VERSION 5.7 ;
  NOWIREEXTENSIONATPIN ON ;
  DIVIDERCHAR "/" ;
  BUSBITCHARS "[]" ;
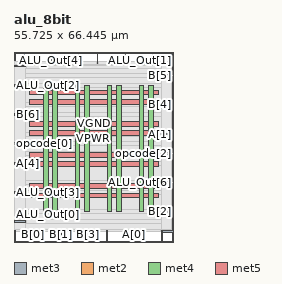
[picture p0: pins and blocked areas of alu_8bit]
MACRO alu_8bit
  CLASS BLOCK ;
  FOREIGN alu_8bit ;
  ORIGIN 0.000 0.000 ;
  SIZE 55.725 BY 66.445 ;
  PIN ALU_Out[0]
    DIRECTION OUTPUT TRISTATE ;
    USE SIGNAL ;
    ANTENNADIFFAREA 0.795200 ;
    PORT
      LAYER met3 ;
        RECT 0.000 6.840 4.000 7.440 ;
    END
  END ALU_Out[0]
  PIN ALU_Out[1]
    DIRECTION OUTPUT TRISTATE ;
    USE SIGNAL ;
    ANTENNADIFFAREA 0.795200 ;
    PORT
      LAYER met2 ;
        RECT 54.830 62.445 55.110 66.445 ;
    END
  END ALU_Out[1]
  PIN ALU_Out[2]
    DIRECTION OUTPUT TRISTATE ;
    USE SIGNAL ;
    ANTENNADIFFAREA 0.795200 ;
    PORT
      LAYER met3 ;
        RECT 0.000 54.440 4.000 55.040 ;
    END
  END ALU_Out[2]
  PIN ALU_Out[3]
    DIRECTION OUTPUT TRISTATE ;
    USE SIGNAL ;
    ANTENNADIFFAREA 0.795200 ;
    PORT
      LAYER met3 ;
        RECT 0.000 17.040 4.000 17.640 ;
    END
  END ALU_Out[3]
  PIN ALU_Out[4]
    DIRECTION OUTPUT TRISTATE ;
    USE SIGNAL ;
    ANTENNADIFFAREA 0.795200 ;
    PORT
      LAYER met2 ;
        RECT 12.970 62.445 13.250 66.445 ;
    END
  END ALU_Out[4]
  PIN ALU_Out[5]
    DIRECTION OUTPUT TRISTATE ;
    USE SIGNAL ;
    ANTENNADIFFAREA 0.795200 ;
    PORT
      LAYER met2 ;
        RECT 22.630 62.445 22.910 66.445 ;
    END
  END ALU_Out[5]
  PIN ALU_Out[6]
    DIRECTION OUTPUT TRISTATE ;
    USE SIGNAL ;
    ANTENNADIFFAREA 0.795200 ;
    PORT
      LAYER met3 ;
        RECT 51.725 20.440 55.725 21.040 ;
    END
  END ALU_Out[6]
  PIN ALU_Out[7]
    DIRECTION OUTPUT TRISTATE ;
    USE SIGNAL ;
    ANTENNADIFFAREA 0.795200 ;
    PORT
      LAYER met2 ;
        RECT 48.390 62.445 48.670 66.445 ;
    END
  END ALU_Out[7]
  PIN A[0]
    DIRECTION INPUT ;
    USE SIGNAL ;
    ANTENNAGATEAREA 0.196500 ;
    PORT
      LAYER met2 ;
        RECT 41.950 0.000 42.230 4.000 ;
    END
  END A[0]
  PIN A[1]
    DIRECTION INPUT ;
    USE SIGNAL ;
    ANTENNAGATEAREA 0.213000 ;
    PORT
      LAYER met3 ;
        RECT 51.725 37.440 55.725 38.040 ;
    END
  END A[1]
  PIN A[2]
    DIRECTION INPUT ;
    USE SIGNAL ;
    ANTENNAGATEAREA 0.213000 ;
    PORT
      LAYER met2 ;
        RECT 38.730 62.445 39.010 66.445 ;
    END
  END A[2]
  PIN A[3]
    DIRECTION INPUT ;
    USE SIGNAL ;
    ANTENNAGATEAREA 0.196500 ;
    PORT
      LAYER met3 ;
        RECT 51.725 3.440 55.725 4.040 ;
    END
  END A[3]
  PIN A[4]
    DIRECTION INPUT ;
    USE SIGNAL ;
    ANTENNAGATEAREA 0.196500 ;
    PORT
      LAYER met3 ;
        RECT 0.000 27.240 4.000 27.840 ;
    END
  END A[4]
  PIN A[5]
    DIRECTION INPUT ;
    USE SIGNAL ;
    ANTENNAGATEAREA 0.196500 ;
    PORT
      LAYER met2 ;
        RECT 3.310 62.445 3.590 66.445 ;
    END
  END A[5]
  PIN A[6]
    DIRECTION INPUT ;
    USE SIGNAL ;
    ANTENNAGATEAREA 0.196500 ;
    PORT
      LAYER met2 ;
        RECT 51.610 0.000 51.890 4.000 ;
    END
  END A[6]
  PIN A[7]
    DIRECTION INPUT ;
    USE SIGNAL ;
    ANTENNAGATEAREA 0.159000 ;
    PORT
      LAYER met2 ;
        RECT 0.090 0.000 0.370 4.000 ;
    END
  END A[7]
  PIN B[0]
    DIRECTION INPUT ;
    USE SIGNAL ;
    ANTENNAGATEAREA 0.196500 ;
    PORT
      LAYER met2 ;
        RECT 6.530 0.000 6.810 4.000 ;
    END
  END B[0]
  PIN B[1]
    DIRECTION INPUT ;
    USE SIGNAL ;
    ANTENNAGATEAREA 0.126000 ;
    PORT
      LAYER met2 ;
        RECT 16.190 0.000 16.470 4.000 ;
    END
  END B[1]
  PIN B[2]
    DIRECTION INPUT ;
    USE SIGNAL ;
    ANTENNAGATEAREA 0.126000 ;
    PORT
      LAYER met3 ;
        RECT 51.725 10.240 55.725 10.840 ;
    END
  END B[2]
  PIN B[3]
    DIRECTION INPUT ;
    USE SIGNAL ;
    ANTENNAGATEAREA 0.196500 ;
    PORT
      LAYER met2 ;
        RECT 25.850 0.000 26.130 4.000 ;
    END
  END B[3]
  PIN B[4]
    DIRECTION INPUT ;
    USE SIGNAL ;
    ANTENNAGATEAREA 0.196500 ;
    PORT
      LAYER met3 ;
        RECT 51.725 47.640 55.725 48.240 ;
    END
  END B[4]
  PIN B[5]
    DIRECTION INPUT ;
    USE SIGNAL ;
    ANTENNAGATEAREA 0.196500 ;
    PORT
      LAYER met3 ;
        RECT 51.725 57.840 55.725 58.440 ;
    END
  END B[5]
  PIN B[6]
    DIRECTION INPUT ;
    USE SIGNAL ;
    ANTENNAGATEAREA 0.196500 ;
    PORT
      LAYER met3 ;
        RECT 0.000 44.240 4.000 44.840 ;
    END
  END B[6]
  PIN B[7]
    DIRECTION INPUT ;
    USE SIGNAL ;
    ANTENNAGATEAREA 0.159000 ;
    PORT
      LAYER met2 ;
        RECT 29.070 62.445 29.350 66.445 ;
    END
  END B[7]
  PIN CarryOut
    DIRECTION OUTPUT TRISTATE ;
    USE SIGNAL ;
    ANTENNADIFFAREA 0.795200 ;
    PORT
      LAYER met2 ;
        RECT 32.290 0.000 32.570 4.000 ;
    END
  END CarryOut
  PIN VGND
    DIRECTION INOUT ;
    USE GROUND ;
    PORT
      LAYER met4 ;
        RECT 13.595 10.640 15.195 54.640 ;
    END
    PORT
      LAYER met4 ;
        RECT 24.750 10.640 26.350 54.640 ;
    END
    PORT
      LAYER met4 ;
        RECT 35.905 10.640 37.505 54.640 ;
    END
    PORT
      LAYER met4 ;
        RECT 47.060 10.640 48.660 54.640 ;
    END
    PORT
      LAYER met5 ;
        RECT 5.280 18.815 50.380 20.415 ;
    END
    PORT
      LAYER met5 ;
        RECT 5.280 29.690 50.380 31.290 ;
    END
    PORT
      LAYER met5 ;
        RECT 5.280 40.565 50.380 42.165 ;
    END
    PORT
      LAYER met5 ;
        RECT 5.280 51.440 50.380 53.040 ;
    END
  END VGND
  PIN VPWR
    DIRECTION INOUT ;
    USE POWER ;
    PORT
      LAYER met4 ;
        RECT 10.295 10.640 11.895 54.640 ;
    END
    PORT
      LAYER met4 ;
        RECT 21.450 10.640 23.050 54.640 ;
    END
    PORT
      LAYER met4 ;
        RECT 32.605 10.640 34.205 54.640 ;
    END
    PORT
      LAYER met4 ;
        RECT 43.760 10.640 45.360 54.640 ;
    END
    PORT
      LAYER met5 ;
        RECT 5.280 15.515 50.380 17.115 ;
    END
    PORT
      LAYER met5 ;
        RECT 5.280 26.390 50.380 27.990 ;
    END
    PORT
      LAYER met5 ;
        RECT 5.280 37.265 50.380 38.865 ;
    END
    PORT
      LAYER met5 ;
        RECT 5.280 48.140 50.380 49.740 ;
    END
  END VPWR
  PIN opcode[0]
    DIRECTION INPUT ;
    USE SIGNAL ;
    ANTENNAGATEAREA 0.213000 ;
    PORT
      LAYER met3 ;
        RECT 0.000 34.040 4.000 34.640 ;
    END
  END opcode[0]
  PIN opcode[1]
    DIRECTION INPUT ;
    USE SIGNAL ;
    ANTENNAGATEAREA 0.213000 ;
    PORT
      LAYER met3 ;
        RECT 0.000 61.240 4.000 61.840 ;
    END
  END opcode[1]
  PIN opcode[2]
    DIRECTION INPUT ;
    USE SIGNAL ;
    ANTENNAGATEAREA 0.159000 ;
    PORT
      LAYER met3 ;
        RECT 51.725 30.640 55.725 31.240 ;
    END
  END opcode[2]
  OBS
      LAYER li1 ;
        RECT 5.520 10.795 50.140 54.485 ;
      LAYER met1 ;
        RECT 0.070 9.900 55.130 54.640 ;
      LAYER met2 ;
        RECT 0.100 62.165 3.030 62.970 ;
        RECT 3.870 62.165 12.690 62.970 ;
        RECT 13.530 62.165 22.350 62.970 ;
        RECT 23.190 62.165 28.790 62.970 ;
        RECT 29.630 62.165 38.450 62.970 ;
        RECT 39.290 62.165 48.110 62.970 ;
        RECT 48.950 62.165 54.550 62.970 ;
        RECT 0.100 4.280 55.100 62.165 ;
        RECT 0.650 3.555 6.250 4.280 ;
        RECT 7.090 3.555 15.910 4.280 ;
        RECT 16.750 3.555 25.570 4.280 ;
        RECT 26.410 3.555 32.010 4.280 ;
        RECT 32.850 3.555 41.670 4.280 ;
        RECT 42.510 3.555 51.330 4.280 ;
        RECT 52.170 3.555 55.100 4.280 ;
      LAYER met3 ;
        RECT 4.400 60.840 51.725 61.690 ;
        RECT 4.000 58.840 51.725 60.840 ;
        RECT 4.000 57.440 51.325 58.840 ;
        RECT 4.000 55.440 51.725 57.440 ;
        RECT 4.400 54.040 51.725 55.440 ;
        RECT 4.000 48.640 51.725 54.040 ;
        RECT 4.000 47.240 51.325 48.640 ;
        RECT 4.000 45.240 51.725 47.240 ;
        RECT 4.400 43.840 51.725 45.240 ;
        RECT 4.000 38.440 51.725 43.840 ;
        RECT 4.000 37.040 51.325 38.440 ;
        RECT 4.000 35.040 51.725 37.040 ;
        RECT 4.400 33.640 51.725 35.040 ;
        RECT 4.000 31.640 51.725 33.640 ;
        RECT 4.000 30.240 51.325 31.640 ;
        RECT 4.000 28.240 51.725 30.240 ;
        RECT 4.400 26.840 51.725 28.240 ;
        RECT 4.000 21.440 51.725 26.840 ;
        RECT 4.000 20.040 51.325 21.440 ;
        RECT 4.000 18.040 51.725 20.040 ;
        RECT 4.400 16.640 51.725 18.040 ;
        RECT 4.000 11.240 51.725 16.640 ;
        RECT 4.000 9.840 51.325 11.240 ;
        RECT 4.000 7.840 51.725 9.840 ;
        RECT 4.400 6.440 51.725 7.840 ;
        RECT 4.000 4.440 51.725 6.440 ;
        RECT 4.000 3.575 51.325 4.440 ;
  END
END alu_8bit
END LIBRARY

